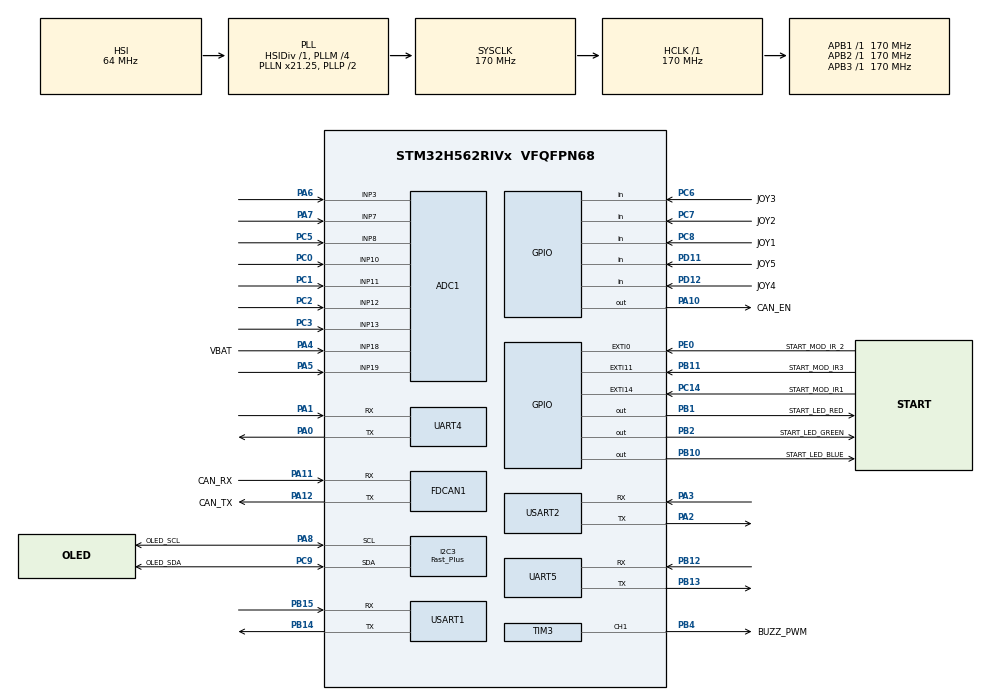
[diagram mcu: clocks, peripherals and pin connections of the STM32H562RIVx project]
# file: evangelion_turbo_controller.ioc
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ADC1.Channel-0\#ChannelRegularConversion=ADC_CHANNEL_3
ADC1.Channel-1\#ChannelRegularConversion=ADC_CHANNEL_7
ADC1.Channel-2\#ChannelRegularConversion=ADC_CHANNEL_8
ADC1.Channel-3\#ChannelRegularConversion=ADC_CHANNEL_10
ADC1.Channel-4\#ChannelRegularConversion=ADC_CHANNEL_11
ADC1.Channel-5\#ChannelRegularConversion=ADC_CHANNEL_12
ADC1.Channel-6\#ChannelRegularConversion=ADC_CHANNEL_13
ADC1.Channel-7\#ChannelRegularConversion=ADC_CHANNEL_18
ADC1.Channel-8\#ChannelRegularConversion=ADC_CHANNEL_19
ADC1.ContinuousConvMode=ENABLE
ADC1.ConversionDataManagement=ADC_CONVERSIONDATA_DMA_CIRCULAR
ADC1.DMAContinuousRequests=ENABLE
ADC1.MonitoredBy-0\#ChannelRegularConversion=__NULL
ADC1.MonitoredBy-1\#ChannelRegularConversion=__NULL
ADC1.MonitoredBy-2\#ChannelRegularConversion=__NULL
ADC1.MonitoredBy-3\#ChannelRegularConversion=__NULL
ADC1.MonitoredBy-4\#ChannelRegularConversion=__NULL
ADC1.MonitoredBy-5\#ChannelRegularConversion=__NULL
ADC1.MonitoredBy-6\#ChannelRegularConversion=__NULL
ADC1.MonitoredBy-7\#ChannelRegularConversion=__NULL
ADC1.MonitoredBy-8\#ChannelRegularConversion=__NULL
ADC1.NbrOfConversion=9
ADC1.NbrOfConversionFlag=1
ADC1.OffsetNumber-0\#ChannelRegularConversion=ADC_OFFSET_NONE
ADC1.OffsetNumber-1\#ChannelRegularConversion=ADC_OFFSET_NONE
ADC1.OffsetNumber-2\#ChannelRegularConversion=ADC_OFFSET_NONE
ADC1.OffsetNumber-3\#ChannelRegularConversion=ADC_OFFSET_NONE
ADC1.OffsetNumber-4\#ChannelRegularConversion=ADC_OFFSET_NONE
ADC1.OffsetNumber-5\#ChannelRegularConversion=ADC_OFFSET_NONE
ADC1.OffsetNumber-6\#ChannelRegularConversion=ADC_OFFSET_NONE
ADC1.OffsetNumber-7\#ChannelRegularConversion=ADC_OFFSET_NONE
ADC1.OffsetNumber-8\#ChannelRegularConversion=ADC_OFFSET_NONE
ADC1.Overrun=ADC_OVR_DATA_OVERWRITTEN
ADC1.Rank-0\#ChannelRegularConversion=1
ADC1.Rank-1\#ChannelRegularConversion=2
ADC1.Rank-2\#ChannelRegularConversion=3
ADC1.Rank-3\#ChannelRegularConversion=4
ADC1.Rank-4\#ChannelRegularConversion=5
ADC1.Rank-5\#ChannelRegularConversion=6
ADC1.Rank-6\#ChannelRegularConversion=7
ADC1.Rank-7\#ChannelRegularConversion=8
ADC1.Rank-8\#ChannelRegularConversion=9
ADC1.SamplingTime-0\#ChannelRegularConversion=ADC_SAMPLETIME_24CYCLES_5
ADC1.SamplingTime-1\#ChannelRegularConversion=ADC_SAMPLETIME_24CYCLES_5
ADC1.SamplingTime-2\#ChannelRegularConversion=ADC_SAMPLETIME_24CYCLES_5
ADC1.SamplingTime-3\#ChannelRegularConversion=ADC_SAMPLETIME_24CYCLES_5
ADC1.SamplingTime-4\#ChannelRegularConversion=ADC_SAMPLETIME_24CYCLES_5
ADC1.SamplingTime-5\#ChannelRegularConversion=ADC_SAMPLETIME_24CYCLES_5
ADC1.SamplingTime-6\#ChannelRegularConversion=ADC_SAMPLETIME_24CYCLES_5
ADC1.SamplingTime-7\#ChannelRegularConversion=ADC_SAMPLETIME_24CYCLES_5
ADC1.SamplingTime-8\#ChannelRegularConversion=ADC_SAMPLETIME_24CYCLES_5
ADC1.master=1
BOOTPATH.BootPathName=LEGACY
BOOTPATH.UserSelectedBootPath=LEGACY
CORTEX_M33_NS.userName=CORTEX_M33
FDCAN1.CalculateBaudRateNominal=1000000
FDCAN1.CalculateTimeBitNominal=1000
FDCAN1.CalculateTimeQuantumNominal=200.0
FDCAN1.DataPrescaler=17
FDCAN1.DataTimeSeg1=2
FDCAN1.DataTimeSeg2=2
FDCAN1.FrameFormat=FDCAN_FRAME_FD_BRS
FDCAN1.NominalPrescaler=34
FDCAN1.NominalTimeSeg1=2
FDCAN1.NominalTimeSeg2=2
GPDMA1.CIRCULARMODE_GPDMACH1=DISABLE
GPDMA1.CIRCULARMODE_GPDMACH2=DISABLE
GPDMA1.CIRCULARMODE_GPDMACH4=DISABLE
GPDMA1.CIRCULARMODE_GPDMACH5=DISABLE
GPDMA1.DATAHANDLING_GPDMACH2=NONE
GPDMA1.DESTBURSTLENGTH_GPDMACH2=1
GPDMA1.DESTDATAWIDTH_GPDMACH2=DMA_DEST_DATAWIDTH_BYTE
GPDMA1.DESTINC_GPDMACH1=DMA_DINC_INCREMENTED
GPDMA1.DESTINC_GPDMACH2=DMA_DINC_INCREMENTED
GPDMA1.DESTINC_GPDMACH4=DMA_DINC_INCREMENTED
GPDMA1.DESTINC_GPDMACH5=DMA_DINC_INCREMENTED
GPDMA1.IPHANDLE_GPDMACH1-SIMPLEREQUEST_GPDMACH1=__NULL
GPDMA1.IPHANDLE_GPDMACH2-SIMPLEREQUEST_GPDMACH2=__NULL
GPDMA1.IPHANDLE_GPDMACH4-SIMPLEREQUEST_GPDMACH4=__NULL
GPDMA1.IPHANDLE_GPDMACH5-SIMPLEREQUEST_GPDMACH5=__NULL
GPDMA1.LINKALLOCATEDPORT_CIRCULAR_GPDMACH4=DMA_LINK_ALLOCATED_PORT1
GPDMA1.LINKALLOCATEDPORT_CIRCULAR_GPDMACH5=DMA_LINK_ALLOCATED_PORT1
GPDMA1.PRIORITY_GPDMACH1=DMA_LOW_PRIORITY_HIGH_WEIGHT
GPDMA1.PRIORITY_GPDMACH2=DMA_LOW_PRIORITY_HIGH_WEIGHT
GPDMA1.PRIORITY_GPDMACH4=DMA_LOW_PRIORITY_HIGH_WEIGHT
GPDMA1.PRIORITY_GPDMACH5=DMA_LOW_PRIORITY_HIGH_WEIGHT
GPDMA1.REQUEST_GPDMACH1=GPDMA1_REQUEST_USART1_RX
GPDMA1.REQUEST_GPDMACH2=GPDMA1_REQUEST_USART2_RX
GPDMA1.REQUEST_GPDMACH4=GPDMA1_REQUEST_UART4_RX
GPDMA1.REQUEST_GPDMACH5=GPDMA1_REQUEST_UART5_RX
GPDMA1.SRCBURSTLENGTH_GPDMACH2=1
GPDMA1.SRCDATAWIDTH_GPDMACH1=DMA_SRC_DATAWIDTH_BYTE
GPDMA1.SRCDATAWIDTH_GPDMACH2=DMA_SRC_DATAWIDTH_BYTE
GPDMA1.SRCINC_GPDMACH2=DMA_SINC_FIXED
GPDMA2.CIRCULARMODE_GPDMACH0=ENABLE
GPDMA2.DESTDATAWIDTH_GPDMACH0=DMA_DEST_DATAWIDTH_HALFWORD
GPDMA2.DESTINC_GPDMACH0=DMA_DINC_INCREMENTED
GPDMA2.IPHANDLE_GPDMACH0-SIMPLEREQUEST_GPDMACH0=__NULL
GPDMA2.LINKALLOCATEDPORT_CIRCULAR_GPDMACH0=DMA_LINK_ALLOCATED_PORT1
GPDMA2.PRIORITY_LL_CIRCULAR_GPDMACH0=DMA_LOW_PRIORITY_MID_WEIGHT
GPDMA2.REQUEST_GPDMACH0=GPDMA2_REQUEST_ADC1
GPDMA2.SRCDATAWIDTH_GPDMACH0=DMA_SRC_DATAWIDTH_HALFWORD
I2C3.I2C_Speed_Mode=I2C_Fast_Plus
I2C3.Timing=0x00802172
Mcu.Family=STM32H5
Mcu.Name=STM32H562RIVx
Mcu.Package=VFQFPN68
NVIC.FDCAN1_IT0_IRQn=true\:0\:0\:false\:false\:true\:true\:true\:true
NVIC.FDCAN1_IT1_IRQn=true\:0\:0\:false\:false\:true\:true\:true\:true
NVIC.GPDMA1_Channel1_IRQn=true\:0\:0\:false\:false\:true\:false\:true\:true
NVIC.GPDMA1_Channel2_IRQn=true\:0\:0\:false\:false\:true\:false\:true\:true
NVIC.GPDMA1_Channel4_IRQn=true\:0\:0\:false\:false\:true\:false\:true\:true
NVIC.GPDMA1_Channel5_IRQn=true\:0\:0\:false\:false\:true\:false\:true\:true
NVIC.GPDMA2_Channel0_IRQn=true\:0\:0\:false\:false\:true\:false\:true\:true
NVIC.I2C3_ER_IRQn=true\:0\:0\:false\:false\:true\:true\:true\:true
NVIC.I2C3_EV_IRQn=true\:0\:0\:false\:false\:true\:true\:true\:true
NVIC.PriorityGroup=NVIC_PRIORITYGROUP_4
NVIC.TIM15_IRQn=true\:0\:0\:false\:false\:true\:true\:true\:true
NVIC.TIM16_IRQn=true\:0\:0\:false\:false\:true\:true\:true\:true
NVIC.TIM17_IRQn=true\:0\:0\:false\:false\:true\:true\:true\:true
NVIC.UART4_IRQn=true\:0\:0\:false\:false\:true\:true\:true\:true
NVIC.UART5_IRQn=true\:0\:0\:false\:false\:true\:true\:true\:true
NVIC.USART1_IRQn=true\:0\:0\:false\:false\:true\:true\:true\:true
NVIC.USART2_IRQn=true\:0\:0\:false\:false\:true\:true\:true\:true
PA0.Mode=Asynchronous
PA0.Signal=UART4_TX
PA1.Mode=Asynchronous
PA1.PinAttribute=Free
PA1.Signal=UART4_RX
PA10.GPIO_Label=CAN_EN
PA10.PinAttribute=Free
PA10.Signal=GPIO_Output
PA11.GPIO_Label=CAN_RX
PA11.Mode=FDCAN_Activate
PA11.PinAttribute=Free
PA11.Signal=FDCAN1_RX
PA12.GPIO_Label=CAN_TX
PA12.Mode=FDCAN_Activate
PA12.PinAttribute=Free
PA12.Signal=FDCAN1_TX
PA13(JTMS/SWDIO).Mode=Serial_Wire
PA13(JTMS/SWDIO).Signal=DEBUG_JTMS-SWDIO
PA14(JTCK/SWCLK).Mode=Serial_Wire
PA14(JTCK/SWCLK).Signal=DEBUG_JTCK-SWCLK
PA2.Mode=Asynchronous
PA2.PinAttribute=Free
PA2.Signal=USART2_TX
PA3.Mode=Asynchronous
PA3.PinAttribute=Free
PA3.Signal=USART2_RX
PA4.GPIO_Label=VBAT
PA4.PinAttribute=Free
PA4.Signal=ADCx_INP18
PA5.PinAttribute=Free
PA5.Signal=ADCx_INP19
PA6.PinAttribute=Free
PA6.Signal=ADCx_INP3
PA7.PinAttribute=Free
PA7.Signal=ADCx_INP7
PA8.GPIO_Label=OLED_SCL
PA8.Mode=I2C
PA8.PinAttribute=Free
PA8.Signal=I2C3_SCL
PB1.GPIO_Label=START_LED_RED
PB1.PinAttribute=Free
PB1.Signal=GPIO_Output
PB10.GPIO_Label=START_LED_BLUE
PB10.PinAttribute=Free
PB10.Signal=GPIO_Output
PB11.GPIO_Label=START_MOD_IR3
PB11.PinAttribute=Free
PB11.Signal=GPXTI11
PB12.Mode=Asynchronous
PB12.PinAttribute=Free
PB12.Signal=UART5_RX
PB13.Mode=Asynchronous
PB13.PinAttribute=Free
PB13.Signal=UART5_TX
PB14.Mode=Asynchronous
PB14.PinAttribute=Free
PB14.Signal=USART1_TX
PB15.Mode=Asynchronous
PB15.PinAttribute=Free
PB15.Signal=USART1_RX
PB2.GPIO_Label=START_LED_GREEN
PB2.PinAttribute=Free
PB2.Signal=GPIO_Output
PB4(NJTRST).GPIO_Label=BUZZ_PWM
PB4(NJTRST).PinAttribute=Free
PB4(NJTRST).Signal=S_TIM3_CH1
PC0.PinAttribute=Free
PC0.Signal=ADCx_INP10
PC1.Signal=ADCx_INP11
PC14-OSC32_IN(OSC32_IN).GPIO_Label=START_MOD_IR1
PC14-OSC32_IN(OSC32_IN).Signal=GPXTI14
PC2.Signal=ADCx_INP12
PC3.Signal=ADCx_INP13
PC5.PinAttribute=Free
PC5.Signal=ADCx_INP8
PC6.GPIO_Label=JOY3
PC6.PinAttribute=Free
PC6.Signal=GPIO_Input
PC7.GPIO_Label=JOY2
PC7.PinAttribute=Free
PC7.Signal=GPIO_Input
PC8.GPIO_Label=JOY1
PC8.PinAttribute=Free
PC8.Signal=GPIO_Input
PC9.GPIO_Label=OLED_SDA
PC9.Mode=I2C
PC9.PinAttribute=Free
PC9.Signal=I2C3_SDA
PD11.GPIO_Label=JOY5
PD11.PinAttribute=Free
PD11.Signal=GPIO_Input
PD12.GPIO_Label=JOY4
PD12.PinAttribute=Free
PD12.Signal=GPIO_Input
PE0.GPIO_Label=START_MOD_IR_2
PE0.PinAttribute=Free
PE0.Signal=GPXTI0
ProjectManager.HeapSize=0x200
ProjectManager.StackSize=0x400
ProjectManager.TargetToolchain=STM32CubeIDE
RCC.ADCFreq_Value=170000000
RCC.AHBFreq_Value=170000000
RCC.APB1Freq_Value=170000000
RCC.APB1TimFreq_Value=170000000
RCC.APB2Freq_Value=170000000
RCC.APB2TimFreq_Value=170000000
RCC.APB3Freq_Value=170000000
RCC.CSI_VALUE=4000000
RCC.CortexFreq_Value=170000000
RCC.EPOD_VALUE=64000000
RCC.FDCANClockSelection=RCC_FDCANCLKSOURCE_PLL1Q
RCC.HCLKFreq_Value=170000000
RCC.HSE_Timout=200
RCC.HSE_VALUE=48000000
RCC.HSI48_VALUE=48000000
RCC.HSIDiv=RCC_HSI_DIV1
RCC.HSI_VALUE=64000000
RCC.LSE_VALUE=32768
RCC.LSIRC_VALUE=32000
RCC.PLL2FRACN=0
RCC.PLL2Source=RCC_PLL2_SOURCE_HSI
RCC.PLL3FRACN=0
RCC.PLL3Source=RCC_PLL3_SOURCE_HSI
RCC.PLL3_VCI_Range-AdvancedSettings=RCC_PLL3_VCIRANGE_0
RCC.PLLFRACN=2048
RCC.PLLM=4
RCC.PLLN=21
RCC.PLLSourceVirtual=RCC_PLL1_SOURCE_HSI
RCC.SYSCLKFreq_VALUE=170000000
RCC.SYSCLKSource=RCC_SYSCLKSOURCE_PLLCLK
RCC.USBFreq_Value=48000000
RCC.VCOOutputFreq_Value=340000000
SH.ADCx_INP10.0=ADC1_INP10,IN10-Single-Ended
SH.ADCx_INP11.0=ADC1_INP11,IN11-Single-Ended
SH.ADCx_INP12.0=ADC1_INP12,IN12-Single-Ended
SH.ADCx_INP13.0=ADC1_INP13,IN13-Single-Ended
SH.ADCx_INP18.0=ADC1_INP18,IN18-Single-Ended
SH.ADCx_INP19.0=ADC1_INP19,IN19-Single-Ended
SH.ADCx_INP3.0=ADC1_INP3,IN3-Single-Ended
SH.ADCx_INP7.0=ADC1_INP7,IN7-Single-Ended
SH.ADCx_INP8.0=ADC1_INP8,IN8-Single-Ended
SH.S_TIM3_CH1.0=TIM3_CH1,PWM Generation1 CH1
TIM15.PeriodNoDither=10000-1
TIM15.Prescaler=34000-1
TIM16.PeriodNoDither=1000-1
TIM16.Prescaler=170-1
TIM17.PeriodNoDither=1000-1
TIM17.Prescaler=1700-1
TIM3.Channel-PWM\ Generation1\ CH1=TIM_CHANNEL_1
USART1.VirtualMode-Asynchronous=VM_ASYNC
USART2.VirtualMode-Asynchronous=VM_ASYNC
VP_BOOTPATH_VS_BOOTPATH.Mode=BP_Activate
VP_CORTEX_M33_NS_VS_Hclk.Mode=Hclk_Mode
VP_GPDMA1_VS_GPDMACH1.Mode=SIMPLEREQUEST_GPDMACH1
VP_GPDMA1_VS_GPDMACH2.Mode=SIMPLEREQUEST_GPDMACH2
VP_GPDMA1_VS_GPDMACH4.Mode=SIMPLEREQUEST_GPDMACH4
VP_GPDMA1_VS_GPDMACH5.Mode=SIMPLEREQUEST_GPDMACH5
VP_GPDMA2_VS_GPDMACH0.Mode=SIMPLEREQUEST_GPDMACH0
VP_MEMORYMAP_VS_MEMORYMAP.Mode=CurAppReg
VP_PWR_VS_LPOM.Mode=PowerOptimisation
VP_PWR_VS_SECSignals.Mode=Security/Privilege
VP_TIM15_VS_ClockSourceINT.Mode=Internal
VP_TIM16_VS_ClockSourceINT.Mode=Enable_Timer
VP_TIM17_VS_ClockSourceINT.Mode=Enable_Timer
board=custom

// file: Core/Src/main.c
/* USER CODE BEGIN Header */
/**
  ******************************************************************************
  * @file           : main.c
  * @brief          : Main program body
  ******************************************************************************
  * @attention
  *
  * Copyright (c) 2026 STMicroelectronics.
  * All rights reserved.
  *
  * This software is licensed under terms that can be found in the LICENSE file
  * in the root directory of this software component.
  * If no LICENSE file comes with this software, it is provided AS-IS.
  *
  ******************************************************************************
  */
/* USER CODE END Header */
#include "main.h"

/* USER CODE BEGIN Includes */
#include "stdlib.h"
#include "MY_INCLUDES.h"
/* USER CODE END Includes */

/* USER CODE BEGIN PD */
#define CAN_SELF_ID 0x0A
#define CAN_MOTOR_DRIVER_A_ID 0x0B
#define CAN_MOTOR_DRIVER_B_ID 0x0C

#define DMA_HANDLE_UART1 &handle_GPDMA1_Channel1
#define DMA_HANDLE_UART2 &handle_GPDMA1_Channel2
#define DMA_HANDLE_UART4 &handle_GPDMA1_Channel4
#define DMA_HANDLE_UART5 &handle_GPDMA1_Channel5
/* USER CODE END PD */

/* USER CODE BEGIN PM */
typedef struct {
	uint8_t DONT_USE_MOTORS;
	uint8_t ALWAYS_IN_BATTLE;
	uint8_t IGNORE_START_MODULE;
	uint8_t LINE_SENSORS_ALWAYS_IN;
	uint8_t IGNORE_ACCEL;
	uint8_t DONT_INITIALIZE_LIDARS;
} Settings_t;

typedef enum {
	IN,
	OUT
} LineState_t;

typedef enum {
	STRAIGHT,
	CURVE,
	FOLLOW_LINER, //todo MRUGNIJ TYLE RAZY JAKI TRYB PO GUZIKU?
} RobotAttackMode_t;

typedef enum
{
	IDLE,
	ATTACK,
	BEFORE_ATTACK_TASK
} RobotState_t;

typedef enum {
	NOTHING,
	UP_LEFT,
	UP_RIGHT,
	DOWN_LEFT,
	DOWN_RIGHT,
	CENTER,
	BUTTON_REBOUNCE,
} JoystickMode_t;

typedef struct {
	LineState_t Line;
	uint16_t RawLineA;
	uint16_t RawLineB;
    uint16_t Distance;
    uint16_t LidarAmp;
    uint16_t LidarTemp;
} SensorData_t;

typedef struct {
	uint8_t Switch1;
	uint8_t Switch2;
	uint8_t Switch3;
	JoystickMode_t Joystick;
	uint8_t MenuOption;
} Interface_t;

typedef struct
{
	int16_t x;
	int16_t y;
	int16_t z;
	int16_t peak;
} Vector_t;

typedef struct {
	uint8_t inBattle;
	RobotAttackMode_t AttackMode;
	uint16_t Voltage;
	uint16_t CellVoltage;
	RobotState_t State;
	Interface_t Interface;
	uint8_t BattType;
} RobotData_t;

typedef struct {
	uint8_t CurrentAddres;
	uint8_t Started;
	uint8_t StartedViaInterface;
	uint8_t StartedViaSwitch;
	uint16_t Delay;
	uint16_t VolatileDelayTimer;
} StartModData_t;

typedef struct
{
	int8_t L;
	int8_t R;
} Speed_t;

typedef struct
{
	Speed_t Requested;
	Speed_t Set;
} MotorSpeed_t;

typedef struct {
    const char *name;
    uint8_t id;
} MenuOption_t;

/* USER CODE END PM */

ADC_HandleTypeDef hadc1;
DMA_NodeTypeDef Node_GPDMA2_Channel0;
DMA_QListTypeDef List_GPDMA2_Channel0;
DMA_HandleTypeDef handle_GPDMA2_Channel0;

FDCAN_HandleTypeDef hfdcan1;

I2C_HandleTypeDef hi2c3;

TIM_HandleTypeDef htim3;
TIM_HandleTypeDef htim15;
TIM_HandleTypeDef htim16;
TIM_HandleTypeDef htim17;

UART_HandleTypeDef huart4;
UART_HandleTypeDef huart5;
UART_HandleTypeDef huart1;
UART_HandleTypeDef huart2;
DMA_HandleTypeDef handle_GPDMA1_Channel4;
DMA_HandleTypeDef handle_GPDMA1_Channel5;
DMA_HandleTypeDef handle_GPDMA1_Channel1;
DMA_HandleTypeDef handle_GPDMA1_Channel2;

/* USER CODE BEGIN PV */
//CAN
FDCAN_RxHeaderTypeDef 		CAN_RX_Header; 		//CAN Bus Transmit Header
FDCAN_TxHeaderTypeDef 		CAN_TX_Header; 		//CAN Bus Receive Header
uint8_t                     CAN_TX[8];
uint8_t                     CAN_RX[8];
FDCAN_FilterTypeDef 		CAN_Filter;

volatile int32_t dupa=-21;
uint16_t actual_init_freq=FREQ_STARTING;
int16_t ERROR_FLAG=0;

//sensors
uint8_t  UART1_RX[9];
uint8_t  UART2_RX[9];
uint8_t  UART4_RX[9];
uint8_t  UART5_RX[9];
uint8_t  UART_TX[9];

SensorData_t FrontLeft={0};
SensorData_t FrontRight={0};
SensorData_t BackLeft={0};
SensorData_t BackRight={0};
RobotData_t Eva={0};
MotorSpeed_t Motors={0};
StartModData_t StartMod={0};
Settings_t Settings={0};

uint8_t lastSeen = LEFT;
uint8_t before_attack_rotation_direction = LEFT;

volatile uint16_t ADC_BUFFER[9];
float BATTERY_CONSTANT;

uint8_t FLAG_BLINK_RED = 0;
uint8_t FLAG_BLINK_BLUE = 0;
uint8_t FLAG_BLINK_GREEN = 0;

/* USER CODE END PV */

void SystemClock_Config(void);
static void MX_GPIO_Init(void);
static void MX_GPDMA1_Init(void);
static void MX_GPDMA2_Init(void);
static void MX_ADC1_Init(void);
static void MX_FDCAN1_Init(void);
static void MX_I2C3_Init(void);
static void MX_TIM3_Init(void);
static void MX_UART4_Init(void);
static void MX_UART5_Init(void);
static void MX_USART2_UART_Init(void);
static void MX_USART1_UART_Init(void);
static void MX_TIM16_Init(void);
static void MX_TIM17_Init(void);
static void MX_TIM15_Init(void);
/* USER CODE BEGIN PFP */
static void LIDARS_INIT(UART_HandleTypeDef *huart, DMA_HandleTypeDef *hdma, uint8_t *RX);
static void PLAY_FREQ(uint16_t f_hz);
static void COOKED(uint8_t error_code);
static void SORT(uint16_t *array, uint8_t length);
static void GET_LINE_SENSORS(void);
static void GET_START_MOD(void);
static void BATTLE(void);
static void WATCHDOG(void);
static void GET_LAST_SEEN_ROTATIONE(void);
static void TASK_BEFORE_ATTACK(void);
static void LED_BLINK_INTERUPT(void);
static void SET_MOTORS(int8_t l, int8_t r);
/* USER CODE END PFP */

int main(void)
{

  /* MCU Configuration--------------------------------------------------------*/

  /* Reset of all peripherals, Initializes the Flash interface and the Systick. */
  HAL_Init();

  /* USER CODE BEGIN Init */
  HAL_Delay(100);
  /* USER CODE END Init */

  /* Configure the system clock */
  SystemClock_Config();

  /* Initialize all configured peripherals */
  MX_GPIO_Init();
  MX_GPDMA1_Init();
  MX_GPDMA2_Init();
  MX_ADC1_Init();
  MX_FDCAN1_Init();
  MX_I2C3_Init();
  MX_TIM3_Init();
  MX_UART4_Init();
  MX_UART5_Init();
  MX_USART2_UART_Init();
  MX_USART1_UART_Init();
  MX_TIM16_Init();
  MX_TIM17_Init();
  MX_TIM15_Init();
  /* USER CODE BEGIN 2 */

  CAN_Filter.IdType = FDCAN_STANDARD_ID;
  CAN_Filter.FilterIndex = 0;
  CAN_Filter.FilterType = FDCAN_FILTER_DISABLE;
  CAN_Filter.FilterConfig = FDCAN_FILTER_TO_RXFIFO0;
  CAN_Filter.FilterID1 = 0;
  CAN_Filter.FilterID2 = 0;

 // CAN_TX_Header.Identifier = CAN_SELF_ID;
  CAN_TX_Header.Identifier = 0x0B;
  CAN_TX_Header.IdType = FDCAN_STANDARD_ID;
  CAN_TX_Header.TxFrameType = FDCAN_DATA_FRAME;
  CAN_TX_Header.DataLength = FDCAN_DLC_BYTES_8;
  CAN_TX_Header.ErrorStateIndicator = FDCAN_ESI_ACTIVE;
  CAN_TX_Header.BitRateSwitch = FDCAN_BRS_ON;
  CAN_TX_Header.FDFormat = FDCAN_FD_CAN;
  CAN_TX_Header.TxEventFifoControl = FDCAN_NO_TX_EVENTS;
  CAN_TX_Header.MessageMarker = 0;

  BATTERY_CONSTANT = ((Voltage_Resistor_Top + Voltage_Resistor_Bottom) / Voltage_Resistor_Bottom) * Reference_Voltage / 4096;

  Settings.ALWAYS_IN_BATTLE = DEFAULT_SETTING_ALWAYS_IN_BATTLE;
  Settings.DONT_INITIALIZE_LIDARS = DEFAULT_SETTING_DONT_INITIALIZE_LIDARS;
  Settings.DONT_USE_MOTORS = DEFAULT_SETTING_DONT_USE_MOTORS;
  Settings.IGNORE_START_MODULE = DEFAULT_SETTING_IGNORE_START_MODULE;

  lastSeen = LEFT;

  //HAL_FDCAN_Start(&hfdcan1);
  //HAL_FDCAN_ActivateNotification(&hfdcan1, FDCAN_IT_RX_FIFO0_NEW_MESSAGE, 0);

  //CAN_TX_Header.Identifier = CAN_MOTOR_DRIVER_A_ID;
  /*
  while(true)
  {
	  CAN_TX[0] = 0x1C;
	  CAN_TX[1] = 0x1C;
	  HAL_FDCAN_AddMessageToTxFifoQ(&hfdcan1, &CAN_TX_Header, CAN_TX);
	  HAL_Delay(1000);
  }

  */
    //GPIO LED MISC
	actual_init_freq = actual_init_freq + FREQ_STEP_INIT;
	PLAY_FREQ(actual_init_freq);
	HAL_GPIO_WritePin(START_LED_RED_GPIO_Port, START_LED_RED_Pin, 0);
	HAL_GPIO_WritePin(START_LED_BLUE_GPIO_Port, START_LED_BLUE_Pin, 0);
	HAL_GPIO_WritePin(START_LED_GREEN_GPIO_Port, START_LED_GREEN_Pin, 1);

	//LUNAS
	LIDARS_INIT(&huart2, DMA_HANDLE_UART2, UART2_RX);

	//Interrupts
	HAL_TIM_Base_Start_IT(&htim15); //0.5Hz
	HAL_TIM_Base_Start_IT(&htim16); //1000Hz
	HAL_TIM_Base_Start_IT(&htim17); //100Hz

	//ADC
	if (HAL_ADCEx_Calibration_Start(&hadc1, ADC_SINGLE_ENDED) != HAL_OK)
	  COOKED(ADC_INIT_ERR);
	HAL_Delay(50);

	if (HAL_ADC_Start_DMA(&hadc1, (uint32_t*)ADC_BUFFER, 9) != HAL_OK)
	  COOKED(ADC_INIT_ERR);
  /* USER CODE END 2 */

  /* Infinite loop */
  while (1)
  {

  }
}

void SystemClock_Config(void)
{
  RCC_OscInitTypeDef RCC_OscInitStruct = {0};
  RCC_ClkInitTypeDef RCC_ClkInitStruct = {0};

  /** Configure the main internal regulator output voltage
  */
  __HAL_PWR_VOLTAGESCALING_CONFIG(PWR_REGULATOR_VOLTAGE_SCALE1);

  while(!__HAL_PWR_GET_FLAG(PWR_FLAG_VOSRDY)) {}

  /** Initializes the RCC Oscillators according to the specified parameters
  * in the RCC_OscInitTypeDef structure.
  */
  RCC_OscInitStruct.OscillatorType = RCC_OSCILLATORTYPE_HSI;
  RCC_OscInitStruct.HSIState = RCC_HSI_ON;
  RCC_OscInitStruct.HSIDiv = RCC_HSI_DIV1;
  RCC_OscInitStruct.HSICalibrationValue = RCC_HSICALIBRATION_DEFAULT;
  RCC_OscInitStruct.PLL.PLLState = RCC_PLL_ON;
  RCC_OscInitStruct.PLL.PLLSource = RCC_PLL1_SOURCE_HSI;
  RCC_OscInitStruct.PLL.PLLM = 4;
  RCC_OscInitStruct.PLL.PLLN = 21;
  RCC_OscInitStruct.PLL.PLLP = 2;
  RCC_OscInitStruct.PLL.PLLQ = 2;
  RCC_OscInitStruct.PLL.PLLR = 2;
  RCC_OscInitStruct.PLL.PLLRGE = RCC_PLL1_VCIRANGE_3;
  RCC_OscInitStruct.PLL.PLLVCOSEL = RCC_PLL1_VCORANGE_WIDE;
  RCC_OscInitStruct.PLL.PLLFRACN = 2048;
  if (HAL_RCC_OscConfig(&RCC_OscInitStruct) != HAL_OK)
  {
    Error_Handler();
  }

  /** Initializes the CPU, AHB and APB buses clocks
  */
  RCC_ClkInitStruct.ClockType = RCC_CLOCKTYPE_HCLK|RCC_CLOCKTYPE_SYSCLK
                              |RCC_CLOCKTYPE_PCLK1|RCC_CLOCKTYPE_PCLK2
                              |RCC_CLOCKTYPE_PCLK3;
  RCC_ClkInitStruct.SYSCLKSource = RCC_SYSCLKSOURCE_PLLCLK;
  RCC_ClkInitStruct.AHBCLKDivider = RCC_SYSCLK_DIV1;
  RCC_ClkInitStruct.APB1CLKDivider = RCC_HCLK_DIV1;
  RCC_ClkInitStruct.APB2CLKDivider = RCC_HCLK_DIV1;
  RCC_ClkInitStruct.APB3CLKDivider = RCC_HCLK_DIV1;

  if (HAL_RCC_ClockConfig(&RCC_ClkInitStruct, FLASH_LATENCY_4) != HAL_OK)
  {
    Error_Handler();
  }

  /** Configure the programming delay
  */
  __HAL_FLASH_SET_PROGRAM_DELAY(FLASH_PROGRAMMING_DELAY_2);
}

static void MX_ADC1_Init(void)
{

  ADC_ChannelConfTypeDef sConfig = {0};

  /** Common config
  */
  hadc1.Instance = ADC1;
  hadc1.Init.ClockPrescaler = ADC_CLOCK_ASYNC_DIV4;
  hadc1.Init.Resolution = ADC_RESOLUTION_12B;
  hadc1.Init.DataAlign = ADC_DATAALIGN_RIGHT;
  hadc1.Init.ScanConvMode = ADC_SCAN_ENABLE;
  hadc1.Init.EOCSelection = ADC_EOC_SINGLE_CONV;
  hadc1.Init.LowPowerAutoWait = DISABLE;
  hadc1.Init.ContinuousConvMode = ENABLE;
  hadc1.Init.NbrOfConversion = 9;
  hadc1.Init.DiscontinuousConvMode = DISABLE;
  hadc1.Init.ExternalTrigConv = ADC_SOFTWARE_START;
  hadc1.Init.ExternalTrigConvEdge = ADC_EXTERNALTRIGCONVEDGE_NONE;
  hadc1.Init.DMAContinuousRequests = ENABLE;
  hadc1.Init.SamplingMode = ADC_SAMPLING_MODE_NORMAL;
  hadc1.Init.Overrun = ADC_OVR_DATA_OVERWRITTEN;
  hadc1.Init.OversamplingMode = DISABLE;
  if (HAL_ADC_Init(&hadc1) != HAL_OK)
  {
    Error_Handler();
  }

  /** Configure Regular Channel
  */
  sConfig.Channel = ADC_CHANNEL_3;
  sConfig.Rank = ADC_REGULAR_RANK_1;
  sConfig.SamplingTime = ADC_SAMPLETIME_24CYCLES_5;
  sConfig.SingleDiff = ADC_SINGLE_ENDED;
  sConfig.OffsetNumber = ADC_OFFSET_NONE;
  sConfig.Offset = 0;
  if (HAL_ADC_ConfigChannel(&hadc1, &sConfig) != HAL_OK)
  {
    Error_Handler();
  }

  /** Configure Regular Channel
  */
  sConfig.Channel = ADC_CHANNEL_7;
  sConfig.Rank = ADC_REGULAR_RANK_2;
  if (HAL_ADC_ConfigChannel(&hadc1, &sConfig) != HAL_OK)
  {
    Error_Handler();
  }

  /** Configure Regular Channel
  */
  sConfig.Channel = ADC_CHANNEL_8;
  sConfig.Rank = ADC_REGULAR_RANK_3;
  if (HAL_ADC_ConfigChannel(&hadc1, &sConfig) != HAL_OK)
  {
    Error_Handler();
  }

  /** Configure Regular Channel
  */
  sConfig.Channel = ADC_CHANNEL_10;
  sConfig.Rank = ADC_REGULAR_RANK_4;
  if (HAL_ADC_ConfigChannel(&hadc1, &sConfig) != HAL_OK)
  {
    Error_Handler();
  }

  /** Configure Regular Channel
  */
  sConfig.Channel = ADC_CHANNEL_11;
  sConfig.Rank = ADC_REGULAR_RANK_5;
  if (HAL_ADC_ConfigChannel(&hadc1, &sConfig) != HAL_OK)
  {
    Error_Handler();
  }

  /** Configure Regular Channel
  */
  sConfig.Channel = ADC_CHANNEL_12;
  sConfig.Rank = ADC_REGULAR_RANK_6;
  if (HAL_ADC_ConfigChannel(&hadc1, &sConfig) != HAL_OK)
  {
    Error_Handler();
  }

  /** Configure Regular Channel
  */
  sConfig.Channel = ADC_CHANNEL_13;
  sConfig.Rank = ADC_REGULAR_RANK_7;
  if (HAL_ADC_ConfigChannel(&hadc1, &sConfig) != HAL_OK)
  {
    Error_Handler();
  }

  /** Configure Regular Channel
  */
  sConfig.Channel = ADC_CHANNEL_18;
  sConfig.Rank = ADC_REGULAR_RANK_8;
  if (HAL_ADC_ConfigChannel(&hadc1, &sConfig) != HAL_OK)
  {
    Error_Handler();
  }

  /** Configure Regular Channel
  */
  sConfig.Channel = ADC_CHANNEL_19;
  sConfig.Rank = ADC_REGULAR_RANK_9;
  if (HAL_ADC_ConfigChannel(&hadc1, &sConfig) != HAL_OK)
  {
    Error_Handler();
  }

}

static void MX_FDCAN1_Init(void)
{

  hfdcan1.Instance = FDCAN1;
  hfdcan1.Init.ClockDivider = FDCAN_CLOCK_DIV1;
  hfdcan1.Init.FrameFormat = FDCAN_FRAME_FD_BRS;
  hfdcan1.Init.Mode = FDCAN_MODE_NORMAL;
  hfdcan1.Init.AutoRetransmission = DISABLE;
  hfdcan1.Init.TransmitPause = DISABLE;
  hfdcan1.Init.ProtocolException = DISABLE;
  hfdcan1.Init.NominalPrescaler = 34;
  hfdcan1.Init.NominalSyncJumpWidth = 1;
  hfdcan1.Init.NominalTimeSeg1 = 2;
  hfdcan1.Init.NominalTimeSeg2 = 2;
  hfdcan1.Init.DataPrescaler = 17;
  hfdcan1.Init.DataSyncJumpWidth = 1;
  hfdcan1.Init.DataTimeSeg1 = 2;
  hfdcan1.Init.DataTimeSeg2 = 2;
  hfdcan1.Init.StdFiltersNbr = 0;
  hfdcan1.Init.ExtFiltersNbr = 0;
  hfdcan1.Init.TxFifoQueueMode = FDCAN_TX_FIFO_OPERATION;
  if (HAL_FDCAN_Init(&hfdcan1) != HAL_OK)
  {
    Error_Handler();
  }

}

static void MX_GPDMA1_Init(void)
{

  /* Peripheral clock enable */
  __HAL_RCC_GPDMA1_CLK_ENABLE();

  /* GPDMA1 interrupt Init */
    HAL_NVIC_SetPriority(GPDMA1_Channel1_IRQn, 0, 0);
    HAL_NVIC_EnableIRQ(GPDMA1_Channel1_IRQn);
    HAL_NVIC_SetPriority(GPDMA1_Channel2_IRQn, 0, 0);
    HAL_NVIC_EnableIRQ(GPDMA1_Channel2_IRQn);
    HAL_NVIC_SetPriority(GPDMA1_Channel4_IRQn, 0, 0);
    HAL_NVIC_EnableIRQ(GPDMA1_Channel4_IRQn);
    HAL_NVIC_SetPriority(GPDMA1_Channel5_IRQn, 0, 0);
    HAL_NVIC_EnableIRQ(GPDMA1_Channel5_IRQn);

}

static void MX_GPDMA2_Init(void)
{

  /* Peripheral clock enable */
  __HAL_RCC_GPDMA2_CLK_ENABLE();

  /* GPDMA2 interrupt Init */
    HAL_NVIC_SetPriority(GPDMA2_Channel0_IRQn, 0, 0);
    HAL_NVIC_EnableIRQ(GPDMA2_Channel0_IRQn);

}

static void MX_I2C3_Init(void)
{

  hi2c3.Instance = I2C3;
  hi2c3.Init.Timing = 0x00802172;
  hi2c3.Init.OwnAddress1 = 0;
  hi2c3.Init.AddressingMode = I2C_ADDRESSINGMODE_7BIT;
  hi2c3.Init.DualAddressMode = I2C_DUALADDRESS_DISABLE;
  hi2c3.Init.OwnAddress2 = 0;
  hi2c3.Init.OwnAddress2Masks = I2C_OA2_NOMASK;
  hi2c3.Init.GeneralCallMode = I2C_GENERALCALL_DISABLE;
  hi2c3.Init.NoStretchMode = I2C_NOSTRETCH_DISABLE;
  if (HAL_I2C_Init(&hi2c3) != HAL_OK)
  {
    Error_Handler();
  }

  /** Configure Analogue filter
  */
  if (HAL_I2CEx_ConfigAnalogFilter(&hi2c3, I2C_ANALOGFILTER_ENABLE) != HAL_OK)
  {
    Error_Handler();
  }

  /** Configure Digital filter
  */
  if (HAL_I2CEx_ConfigDigitalFilter(&hi2c3, 0) != HAL_OK)
  {
    Error_Handler();
  }

  /** I2C Fast mode Plus enable
  */
  if (HAL_I2CEx_ConfigFastModePlus(&hi2c3, I2C_FASTMODEPLUS_ENABLE) != HAL_OK)
  {
    Error_Handler();
  }

}

static void MX_TIM3_Init(void)
{

  TIM_MasterConfigTypeDef sMasterConfig = {0};
  TIM_OC_InitTypeDef sConfigOC = {0};

  htim3.Instance = TIM3;
  htim3.Init.Prescaler = 0;
  htim3.Init.CounterMode = TIM_COUNTERMODE_UP;
  htim3.Init.Period = 65535;
  htim3.Init.ClockDivision = TIM_CLOCKDIVISION_DIV1;
  htim3.Init.AutoReloadPreload = TIM_AUTORELOAD_PRELOAD_DISABLE;
  if (HAL_TIM_PWM_Init(&htim3) != HAL_OK)
  {
    Error_Handler();
  }
  sMasterConfig.MasterOutputTrigger = TIM_TRGO_RESET;
  sMasterConfig.MasterSlaveMode = TIM_MASTERSLAVEMODE_DISABLE;
  if (HAL_TIMEx_MasterConfigSynchronization(&htim3, &sMasterConfig) != HAL_OK)
  {
    Error_Handler();
  }
  sConfigOC.OCMode = TIM_OCMODE_PWM1;
  sConfigOC.Pulse = 0;
  sConfigOC.OCPolarity = TIM_OCPOLARITY_HIGH;
  sConfigOC.OCFastMode = TIM_OCFAST_DISABLE;
  if (HAL_TIM_PWM_ConfigChannel(&htim3, &sConfigOC, TIM_CHANNEL_1) != HAL_OK)
  {
    Error_Handler();
  }
  HAL_TIM_MspPostInit(&htim3);

}

static void MX_TIM15_Init(void)
{

  TIM_ClockConfigTypeDef sClockSourceConfig = {0};
  TIM_MasterConfigTypeDef sMasterConfig = {0};

  htim15.Instance = TIM15;
  htim15.Init.Prescaler = 34000-1;
  htim15.Init.CounterMode = TIM_COUNTERMODE_UP;
  htim15.Init.Period = 9999;
  htim15.Init.ClockDivision = TIM_CLOCKDIVISION_DIV1;
  htim15.Init.RepetitionCounter = 0;
  htim15.Init.AutoReloadPreload = TIM_AUTORELOAD_PRELOAD_DISABLE;
  if (HAL_TIM_Base_Init(&htim15) != HAL_OK)
  {
    Error_Handler();
  }
  sClockSourceConfig.ClockSource = TIM_CLOCKSOURCE_INTERNAL;
  if (HAL_TIM_ConfigClockSource(&htim15, &sClockSourceConfig) != HAL_OK)
  {
    Error_Handler();
  }
  sMasterConfig.MasterOutputTrigger = TIM_TRGO_RESET;
  sMasterConfig.MasterSlaveMode = TIM_MASTERSLAVEMODE_DISABLE;
  if (HAL_TIMEx_MasterConfigSynchronization(&htim15, &sMasterConfig) != HAL_OK)
  {
    Error_Handler();
  }

}

static void MX_TIM16_Init(void)
{

  htim16.Instance = TIM16;
  htim16.Init.Prescaler = 170-1;
  htim16.Init.CounterMode = TIM_COUNTERMODE_UP;
  htim16.Init.Period = 999;
  htim16.Init.ClockDivision = TIM_CLOCKDIVISION_DIV1;
  htim16.Init.RepetitionCounter = 0;
  htim16.Init.AutoReloadPreload = TIM_AUTORELOAD_PRELOAD_DISABLE;
  if (HAL_TIM_Base_Init(&htim16) != HAL_OK)
  {
    Error_Handler();
  }

}

static void MX_TIM17_Init(void)
{

  htim17.Instance = TIM17;
  htim17.Init.Prescaler = 1700-1;
  htim17.Init.CounterMode = TIM_COUNTERMODE_UP;
  htim17.Init.Period = 999;
  htim17.Init.ClockDivision = TIM_CLOCKDIVISION_DIV1;
  htim17.Init.RepetitionCounter = 0;
  htim17.Init.AutoReloadPreload = TIM_AUTORELOAD_PRELOAD_DISABLE;
  if (HAL_TIM_Base_Init(&htim17) != HAL_OK)
  {
    Error_Handler();
  }

}

static void MX_UART4_Init(void)
{

  huart4.Instance = UART4;
  huart4.Init.BaudRate = 115200;
  huart4.Init.WordLength = UART_WORDLENGTH_8B;
  huart4.Init.StopBits = UART_STOPBITS_1;
  huart4.Init.Parity = UART_PARITY_NONE;
  huart4.Init.Mode = UART_MODE_TX_RX;
  huart4.Init.HwFlowCtl = UART_HWCONTROL_NONE;
  huart4.Init.OverSampling = UART_OVERSAMPLING_16;
  huart4.Init.OneBitSampling = UART_ONE_BIT_SAMPLE_DISABLE;
  huart4.Init.ClockPrescaler = UART_PRESCALER_DIV1;
  huart4.AdvancedInit.AdvFeatureInit = UART_ADVFEATURE_NO_INIT;
  if (HAL_UART_Init(&huart4) != HAL_OK)
  {
    Error_Handler();
  }
  if (HAL_UARTEx_SetTxFifoThreshold(&huart4, UART_TXFIFO_THRESHOLD_1_8) != HAL_OK)
  {
    Error_Handler();
  }
  if (HAL_UARTEx_SetRxFifoThreshold(&huart4, UART_RXFIFO_THRESHOLD_1_8) != HAL_OK)
  {
    Error_Handler();
  }
  if (HAL_UARTEx_DisableFifoMode(&huart4) != HAL_OK)
  {
    Error_Handler();
  }

}

static void MX_UART5_Init(void)
{

  huart5.Instance = UART5;
  huart5.Init.BaudRate = 115200;
  huart5.Init.WordLength = UART_WORDLENGTH_8B;
  huart5.Init.StopBits = UART_STOPBITS_1;
  huart5.Init.Parity = UART_PARITY_NONE;
  huart5.Init.Mode = UART_MODE_TX_RX;
  huart5.Init.HwFlowCtl = UART_HWCONTROL_NONE;
  huart5.Init.OverSampling = UART_OVERSAMPLING_16;
  huart5.Init.OneBitSampling = UART_ONE_BIT_SAMPLE_DISABLE;
  huart5.Init.ClockPrescaler = UART_PRESCALER_DIV1;
  huart5.AdvancedInit.AdvFeatureInit = UART_ADVFEATURE_NO_INIT;
  if (HAL_UART_Init(&huart5) != HAL_OK)
  {
    Error_Handler();
  }
  if (HAL_UARTEx_SetTxFifoThreshold(&huart5, UART_TXFIFO_THRESHOLD_1_8) != HAL_OK)
  {
    Error_Handler();
  }
  if (HAL_UARTEx_SetRxFifoThreshold(&huart5, UART_RXFIFO_THRESHOLD_1_8) != HAL_OK)
  {
    Error_Handler();
  }
  if (HAL_UARTEx_DisableFifoMode(&huart5) != HAL_OK)
  {
    Error_Handler();
  }

}

static void MX_USART1_UART_Init(void)
{

  huart1.Instance = USART1;
  huart1.Init.BaudRate = 115200;
  huart1.Init.WordLength = UART_WORDLENGTH_8B;
  huart1.Init.StopBits = UART_STOPBITS_1;
  huart1.Init.Parity = UART_PARITY_NONE;
  huart1.Init.Mode = UART_MODE_TX_RX;
  huart1.Init.HwFlowCtl = UART_HWCONTROL_NONE;
  huart1.Init.OverSampling = UART_OVERSAMPLING_16;
  huart1.Init.OneBitSampling = UART_ONE_BIT_SAMPLE_DISABLE;
  huart1.Init.ClockPrescaler = UART_PRESCALER_DIV1;
  huart1.AdvancedInit.AdvFeatureInit = UART_ADVFEATURE_NO_INIT;
  if (HAL_UART_Init(&huart1) != HAL_OK)
  {
    Error_Handler();
  }
  if (HAL_UARTEx_SetTxFifoThreshold(&huart1, UART_TXFIFO_THRESHOLD_1_8) != HAL_OK)
  {
    Error_Handler();
  }
  if (HAL_UARTEx_SetRxFifoThreshold(&huart1, UART_RXFIFO_THRESHOLD_1_8) != HAL_OK)
  {
    Error_Handler();
  }
  if (HAL_UARTEx_DisableFifoMode(&huart1) != HAL_OK)
  {
    Error_Handler();
  }

}

static void MX_USART2_UART_Init(void)
{

  huart2.Instance = USART2;
  huart2.Init.BaudRate = 115200;
  huart2.Init.WordLength = UART_WORDLENGTH_8B;
  huart2.Init.StopBits = UART_STOPBITS_1;
  huart2.Init.Parity = UART_PARITY_NONE;
  huart2.Init.Mode = UART_MODE_TX_RX;
  huart2.Init.HwFlowCtl = UART_HWCONTROL_NONE;
  huart2.Init.OverSampling = UART_OVERSAMPLING_16;
  huart2.Init.OneBitSampling = UART_ONE_BIT_SAMPLE_DISABLE;
  huart2.Init.ClockPrescaler = UART_PRESCALER_DIV1;
  huart2.AdvancedInit.AdvFeatureInit = UART_ADVFEATURE_NO_INIT;
  if (HAL_UART_Init(&huart2) != HAL_OK)
  {
    Error_Handler();
  }
  if (HAL_UARTEx_SetTxFifoThreshold(&huart2, UART_TXFIFO_THRESHOLD_1_8) != HAL_OK)
  {
    Error_Handler();
  }
  if (HAL_UARTEx_SetRxFifoThreshold(&huart2, UART_RXFIFO_THRESHOLD_1_8) != HAL_OK)
  {
    Error_Handler();
  }
  if (HAL_UARTEx_DisableFifoMode(&huart2) != HAL_OK)
  {
    Error_Handler();
  }

}

static void MX_GPIO_Init(void)
{
  GPIO_InitTypeDef GPIO_InitStruct = {0};

  /* GPIO Ports Clock Enable */
  __HAL_RCC_GPIOC_CLK_ENABLE();
  __HAL_RCC_GPIOH_CLK_ENABLE();
  __HAL_RCC_GPIOA_CLK_ENABLE();
  __HAL_RCC_GPIOB_CLK_ENABLE();
  __HAL_RCC_GPIOD_CLK_ENABLE();
  __HAL_RCC_GPIOE_CLK_ENABLE();

  /*Configure GPIO pin Output Level */
  HAL_GPIO_WritePin(GPIOB, START_LED_RED_Pin|START_LED_GREEN_Pin|START_LED_BLUE_Pin, GPIO_PIN_RESET);

  /*Configure GPIO pin Output Level */
  HAL_GPIO_WritePin(DR1_EN_GPIO_Port, DR1_EN_Pin, GPIO_PIN_RESET);

  /*Configure GPIO pin Output Level */
  HAL_GPIO_WritePin(DR2_EN_GPIO_Port, DR2_EN_Pin, GPIO_PIN_RESET);

  /*Configure GPIO pin : START_MOD_IR1_Pin */
  GPIO_InitStruct.Pin = START_MOD_IR1_Pin;
  GPIO_InitStruct.Mode = GPIO_MODE_IT_RISING;
  GPIO_InitStruct.Pull = GPIO_NOPULL;
  HAL_GPIO_Init(START_MOD_IR1_GPIO_Port, &GPIO_InitStruct);

  /*Configure GPIO pins : START_LED_RED_Pin START_LED_GREEN_Pin START_LED_BLUE_Pin */
  GPIO_InitStruct.Pin = START_LED_RED_Pin|START_LED_GREEN_Pin|START_LED_BLUE_Pin;
  GPIO_InitStruct.Mode = GPIO_MODE_OUTPUT_PP;
  GPIO_InitStruct.Pull = GPIO_NOPULL;
  GPIO_InitStruct.Speed = GPIO_SPEED_FREQ_LOW;
  HAL_GPIO_Init(GPIOB, &GPIO_InitStruct);

  /*Configure GPIO pin : START_MOD_IR3_Pin */
  GPIO_InitStruct.Pin = START_MOD_IR3_Pin;
  GPIO_InitStruct.Mode = GPIO_MODE_IT_RISING;
  GPIO_InitStruct.Pull = GPIO_NOPULL;
  HAL_GPIO_Init(START_MOD_IR3_GPIO_Port, &GPIO_InitStruct);

  /*Configure GPIO pins : JOY5_Pin JOY4_Pin */
  GPIO_InitStruct.Pin = JOY5_Pin|JOY4_Pin;
  GPIO_InitStruct.Mode = GPIO_MODE_INPUT;
  GPIO_InitStruct.Pull = GPIO_NOPULL;
  HAL_GPIO_Init(GPIOD, &GPIO_InitStruct);

  /*Configure GPIO pins : JOY3_Pin JOY2_Pin JOY1_Pin */
  GPIO_InitStruct.Pin = JOY3_Pin|JOY2_Pin|JOY1_Pin;
  GPIO_InitStruct.Mode = GPIO_MODE_INPUT;
  GPIO_InitStruct.Pull = GPIO_NOPULL;
  HAL_GPIO_Init(GPIOC, &GPIO_InitStruct);

  /*Configure GPIO pin : DR1_EN_Pin */
  GPIO_InitStruct.Pin = DR1_EN_Pin;
  GPIO_InitStruct.Mode = GPIO_MODE_OUTPUT_PP;
  GPIO_InitStruct.Pull = GPIO_NOPULL;
  GPIO_InitStruct.Speed = GPIO_SPEED_FREQ_LOW;
  HAL_GPIO_Init(DR1_EN_GPIO_Port, &GPIO_InitStruct);

  /*Configure GPIO pin : DR2_EN_Pin */
  GPIO_InitStruct.Pin = DR2_EN_Pin;
  GPIO_InitStruct.Mode = GPIO_MODE_OUTPUT_PP;
  GPIO_InitStruct.Pull = GPIO_NOPULL;
  GPIO_InitStruct.Speed = GPIO_SPEED_FREQ_LOW;
  HAL_GPIO_Init(DR2_EN_GPIO_Port, &GPIO_InitStruct);

  /*Configure GPIO pin : START_MOD_IR_2_Pin */
  GPIO_InitStruct.Pin = START_MOD_IR_2_Pin;
  GPIO_InitStruct.Mode = GPIO_MODE_IT_RISING;
  GPIO_InitStruct.Pull = GPIO_NOPULL;
  HAL_GPIO_Init(START_MOD_IR_2_GPIO_Port, &GPIO_InitStruct);

}

/* USER CODE BEGIN 4 */
void HAL_TIM_PeriodElapsedCallback(TIM_HandleTypeDef *htim)
{
	if(htim->Instance == TIM16) //0.5Hz leds!
	{
		LED_BLINK_INTERUPT();
	}
	if(htim->Instance == TIM16) //1000Hz battlee
	{
	  GET_LINE_SENSORS();
	  GET_LAST_SEEN_ROTATIONE();
	  GET_START_MOD();
	  if(Eva.State == IDLE)
	  {
		  //BATTLE();
	  }
	  if(Eva.State == ATTACK)
	  {
		  //BATTLE();
	  }
	  else if(Eva.State == BEFORE_ATTACK_TASK)
	  {
		  TASK_BEFORE_ATTACK();
	  }
	}

	if(htim->Instance == TIM17) //100hz everything else
	{
	   WATCHDOG();
	}
}

void LED_BLINK_INTERUPT()
{
	if (FLAG_BLINK_RED == 1)
		HAL_GPIO_TogglePin(START_LED_RED_GPIO_Port, START_LED_RED_Pin);
	else
		HAL_GPIO_WritePin(START_LED_RED_GPIO_Port, START_LED_RED_Pin, 0);

	if (FLAG_BLINK_BLUE == 1)
		HAL_GPIO_TogglePin(START_LED_BLUE_GPIO_Port, START_LED_BLUE_Pin);
	else
		HAL_GPIO_WritePin(START_LED_BLUE_GPIO_Port, START_LED_BLUE_Pin, 0);

	if (FLAG_BLINK_GREEN == 1)
		HAL_GPIO_TogglePin(START_LED_GREEN_GPIO_Port, START_LED_GREEN_Pin);
	else
		HAL_GPIO_WritePin(START_LED_GREEN_GPIO_Port, START_LED_GREEN_Pin, 0);

	FLAG_BLINK_RED = 0;
	FLAG_BLINK_BLUE = 0;
	FLAG_BLINK_GREEN = 0;
}

void TASK_BEFORE_ATTACK()
{
	typedef enum {
		ZERO,
		START_WAIT_DELAY,
		INITIAL_ROTATION,
		GO_TO_THE_EDGE,
	} Stage_t;
	static Stage_t taskStage = START_WAIT_DELAY;
	static uint16_t StartDelayTimer=0;

	if(taskStage == ZERO)
	{
		StartDelayTimer=0;
		taskStage = START_WAIT_DELAY;
	}

	if(taskStage == START_WAIT_DELAY)
	{
		StartDelayTimer++;
		if(StartDelayTimer > START_WAITING_TIME)
			taskStage = INITIAL_ROTATION;
	}

	if(taskStage == INITIAL_ROTATION)
	{
		if(before_attack_rotation_direction == LEFT)
		{
			SET_MOTORS(-ROTATE_BEFORE_TASK_SPEED, ROTATE_BEFORE_TASK_SPEED);
			if (BackLeft.Distance < ACKNOWLEDGE_LIDAR_DISTANCE)
			{
				taskStage = GO_TO_THE_EDGE;
			}
		}
		else
		{
			SET_MOTORS(ROTATE_BEFORE_TASK_SPEED, -ROTATE_BEFORE_TASK_SPEED);
			if (BackRight.Distance < ACKNOWLEDGE_LIDAR_DISTANCE)
			{
				taskStage = GO_TO_THE_EDGE;
			}
		}
	}

	if(taskStage == GO_TO_THE_EDGE)
	{
		SET_MOTORS(-GO_TO_LINE_TASK_SPEED, -GO_TO_LINE_TASK_SPEED);
		if(BackLeft.Line == OUT || BackRight.Line == OUT) //reszta? todo
		{
			taskStage = ZERO;
			Eva.State = ATTACK;
		}
	}

}

void SET_MOTORS(int8_t l, int8_t r)
{

	if(Settings.DONT_USE_MOTORS)
		l = r = 0;

	if (SWITCH_MOTORS)
	{
	    int8_t tmp = l;
	    l = r;
	    r = tmp;
	}
	if(REVERSE_RIGHT_MOTOR)
	{
		r = -r;
	}
	if(REVERSE_LEFT_MOTOR)
	{
		l = -l;
	}

	l = l * LEFT_MOTOR_SPEED_MULTIPLIER;
	r = r * RIGHT_MOTOR_SPEED_MULTIPLIER;
}

void GET_LAST_SEEN_ROTATIONE()
{
	if(Eva.State == IDLE)
	{
		if(FrontLeft.Distance <= MIN_LIDAR_DISTANCE)
			lastSeen = LEFT;
		else if(FrontRight.Distance <= MIN_LIDAR_DISTANCE)
			lastSeen = RIGHT;
	}
	else
	{
		if(FrontLeft.Distance <= MAX_LIDAR_DISTANCE)
			lastSeen = LEFT;
		else if(FrontRight.Distance <= MAX_LIDAR_DISTANCE)
			lastSeen = RIGHT;
	}

}

void GET_START_MOD()
{
	Eva.State = IDLE;

	if(false)
	{
		before_attack_rotation_direction = lastSeen;
        Eva.State = BEFORE_ATTACK_TASK;
	}
}

void BATTLE()
{
	//67
}

void COOKED(uint8_t error_code)
//error flag codes less than 200 has priority and HALT
{
	  //TODO buzzer?
	  if(error_code < 200)
	  {
		  ERROR_FLAG = error_code;
		  Error_Handler();
	  }
	  else
	  {
		  ERROR_FLAG = error_code;
	  }
}

void HAL_FDCAN_RxFifo0Callback(FDCAN_HandleTypeDef *hfdcan, uint32_t RxFifo0ITs)
{

	HAL_FDCAN_GetRxMessage(hfdcan, FDCAN_RX_FIFO0, &CAN_RX_Header, CAN_RX);
	HAL_FDCAN_ActivateNotification(hfdcan, FDCAN_IT_RX_FIFO0_NEW_MESSAGE, 0);
}

void LIDARS_INIT(UART_HandleTypeDef *huart, DMA_HandleTypeDef *dma, uint8_t *RX)
{
	uint8_t counter=0;

	//LIDARS OFF
	UART_TX[0] = 0x5A;
	UART_TX[1] = 0x05;
	UART_TX[2] = 0x07;
	UART_TX[3] = 0x00;
	UART_TX[4] = (UART_TX[0] + UART_TX[1] + UART_TX[2] + UART_TX[3]) % 0x100;
	counter=0;
	while(true)
	{
		HAL_UART_Transmit(huart, UART_TX, 5, LIDARS_INIT_UART_TIMEOUT);
		HAL_UART_Receive(huart, RX, 5, LIDARS_INIT_UART_TIMEOUT);

		if(RX[0] == UART_TX[0] && RX[1] == UART_TX[1] && RX[2] == UART_TX[2])
			break;
		if(counter >= MAX_RETRIES_LIDARS_INIT)
			COOKED(LIDARS_INIT_ERR);
		counter++;
	}
	counter=0;
	HAL_Delay(50);

	//LIDARS SET 250Hz
	UART_TX[0] = 0x5A;
	UART_TX[1] = 0x06;
	UART_TX[2] = 0x03;
	UART_TX[3] = 0xFA;
	UART_TX[4] = 0x00;
	UART_TX[5] = (UART_TX[0] + UART_TX[1] + UART_TX[2] + UART_TX[3]) % 0x100;
	counter=0;
	while(true)
	{
		HAL_UART_Transmit(huart, UART_TX, 6, LIDARS_INIT_UART_TIMEOUT);
		HAL_UART_Receive(huart, RX, 6, LIDARS_INIT_UART_TIMEOUT);

		if(RX[0] == UART_TX[0] && RX[1] == UART_TX[1] && RX[2] == UART_TX[2])
			break;
		if(counter >= MAX_RETRIES_LIDARS_INIT)
			COOKED(LIDARS_INIT_ERR);
		counter++;
	}
	counter=0;
	HAL_Delay(50);

	//LIDARS ON
	UART_TX[0] = 0x5A;
	UART_TX[1] = 0x05;
	UART_TX[2] = 0x07;
	UART_TX[3] = 0x01;
	UART_TX[4] = (UART_TX[0] + UART_TX[1] + UART_TX[2] + UART_TX[3]) % 0x100;
	counter=0;
	while(true)
	{
		HAL_UART_Transmit(huart, UART_TX, 5, LIDARS_INIT_UART_TIMEOUT);
		HAL_UART_Receive(huart, RX, 5, LIDARS_INIT_UART_TIMEOUT);

		if(RX[0] == UART_TX[0] && RX[1] == UART_TX[1] && RX[2] == UART_TX[2])
			break;
		if(counter >= MAX_RETRIES_LIDARS_INIT)
			COOKED(LIDARS_INIT_ERR);
		counter++;
	}
	HAL_Delay(50);

	counter=0;
	while(true)
	{

		if(huart->RxState == HAL_UART_STATE_READY && huart->gState == HAL_UART_STATE_READY && huart->ErrorCode == HAL_UART_ERROR_NONE)
			break;
		else if(counter >= MAX_RETRIES_LIDARS_INIT)
			COOKED(LIDARS_INIT_ERR);

		HAL_Delay(LIDARS_INIT_UART_TIMEOUT);
		counter++;
	}

	HAL_Delay(50);

	HAL_UART_AbortReceive(huart);
	__HAL_UART_CLEAR_OREFLAG(huart);
	huart->ErrorCode = HAL_UART_ERROR_NONE;
	huart->RxState   = HAL_UART_STATE_READY;
	if(HAL_UARTEx_ReceiveToIdle_DMA(huart, RX, 9) != HAL_OK)
		COOKED(LIDARS_INIT_ERR);
	__HAL_DMA_DISABLE_IT(dma, DMA_IT_HT);

}

void PLAY_FREQ(uint16_t f_hz)
{
	f_hz = f_hz * ENABLE_BUZZER;
    if (f_hz == 0) {
        __HAL_TIM_SET_COMPARE(&htim3, TIM_CHANNEL_1, 0);
        return;
    }

    // Stały PSC=169 -> licznik 1 MHz (TIMCLK 170 MHz / (169+1))
    __HAL_TIM_SET_PRESCALER(&htim3, 169);

    uint32_t arr = 1000000UL / f_hz;            // okres w tickach 1 MHz
    if (arr == 0) arr = 1;                      // minimalna wartość
    arr -= 1;                                   // rejestrowo

    __HAL_TIM_DISABLE(&htim3);
    __HAL_TIM_SET_AUTORELOAD(&htim3, (uint16_t)arr);
    __HAL_TIM_SET_COMPARE(&htim3, TIM_CHANNEL_1, (uint16_t)(((arr + 1U) >> 1)));
    __HAL_TIM_SET_COUNTER(&htim3, 0);
    __HAL_TIM_ENABLE(&htim3);
    HAL_TIM_PWM_Start(&htim3, TIM_CHANNEL_1);
}

void HAL_UARTEx_RxEventCallback(UART_HandleTypeDef *huart, uint16_t Size)
{
	uint16_t buffor_Dist[LIDARS_FILTERING_ARRAY_SIZE];
	uint16_t buffor_Amp[LIDARS_FILTERING_ARRAY_SIZE];
	uint16_t Dist, Temp, Amp;
	uint8_t j, k;

	if(huart->Instance == USART1)
	{
		for (int i = 1; i < 10; i++)
		{
			if (UART1_RX[(i-1)% 9] == 0x59 && UART1_RX[i%9] == 0x59)
			{
				//DISTANCE
				j = (i + 1) % 9;
				k = (i + 2) % 9;
				Dist = UART1_RX[j] + (UART1_RX[k] << 8);

				//AMPERAGE
				j = (i + 3) % 9;
				k = (i + 4) % 9;
				Amp = UART1_RX[j] + (UART1_RX[k] << 8);

				//TEMPERATURE
				j = (i + 5) % 9;
				k = (i + 6) % 9;
				Temp = UART1_RX[j] + (UART1_RX[k] << 8);

				if(Amp < MIN_AMP_TRESCHOLD)
				{
					Dist = 65000;
				}

				break;
			}
		}

		//=====MEDIAN FILTERING
		static uint16_t window1_Dist[LIDARS_FILTERING_ARRAY_SIZE];
		static uint16_t window1_Amp[LIDARS_FILTERING_ARRAY_SIZE];
		static uint8_t idx1_Dist = 0;
		static uint8_t idx1_Amp = 0;

		//Wstaw nowe wartosci
		window1_Dist[idx1_Dist] = Dist;
		window1_Amp[idx1_Amp] = Amp;

		//Przesun indeksy cyklicznie
		idx1_Dist = (idx1_Dist + 1) % LIDARS_FILTERING_ARRAY_SIZE;
		idx1_Amp = (idx1_Amp + 1) % LIDARS_FILTERING_ARRAY_SIZE;

		//Kopiuj i sortuj w jednej petli
		for (int i = 0; i < LIDARS_FILTERING_ARRAY_SIZE; i++) {
			buffor_Dist[i] = window1_Dist[i];
			buffor_Amp[i] = window1_Amp[i];
		}

		//Sortuj osobno
		SORT(buffor_Dist, LIDARS_FILTERING_ARRAY_SIZE);
		SORT(buffor_Amp, LIDARS_FILTERING_ARRAY_SIZE);

		//Wyciagnij mediany
		Dist = buffor_Dist[(uint8_t)((LIDARS_FILTERING_ARRAY_SIZE - 1) / 2)];
		Amp = buffor_Amp[(uint8_t)((LIDARS_FILTERING_ARRAY_SIZE - 1) / 2)];

		//Save results
		FrontRight.Distance = Dist;
		FrontRight.LidarAmp = Amp;
		FrontRight.LidarTemp = Temp;

		if(HAL_UARTEx_ReceiveToIdle_DMA(&huart1, UART1_RX, 9) != HAL_OK)
			COOKED(LIDARS_INIT_ERR);
		__HAL_DMA_DISABLE_IT(DMA_HANDLE_UART1, DMA_IT_HT);
	}

	if(huart->Instance == USART2)
		{
			for (int i = 1; i < 10; i++)
			{
				if (UART2_RX[(i-1)% 9] == 0x59 && UART2_RX[i%9] == 0x59)
				{
					//DISTANCE
					j = (i + 1) % 9;
					k = (i + 2) % 9;
					Dist = UART2_RX[j] + (UART2_RX[k] << 8);

					//AMPERAGE
					j = (i + 3) % 9;
					k = (i + 4) % 9;
					Amp = UART2_RX[j] + (UART2_RX[k] << 8);

					//TEMPERATURE
					j = (i + 5) % 9;
					k = (i + 6) % 9;
					Temp = UART2_RX[j] + (UART2_RX[k] << 8);

					if(Amp < MIN_AMP_TRESCHOLD)
					{
						Dist = 65000;
					}

					break;
				}
			}

			//=====MEDIAN FILTERING
			static uint16_t window2_Dist[LIDARS_FILTERING_ARRAY_SIZE];
			static uint16_t window2_Amp[LIDARS_FILTERING_ARRAY_SIZE];
			static uint8_t idx2_Dist = 0;
			static uint8_t idx2_Amp = 0;

			//Wstaw nowe wartosci
			window2_Dist[idx2_Dist] = Dist;
			window2_Amp[idx2_Amp] = Amp;

			//Przesun indeksy cyklicznie
			idx2_Dist = (idx2_Dist + 1) % LIDARS_FILTERING_ARRAY_SIZE;
			idx2_Amp = (idx2_Amp + 1) % LIDARS_FILTERING_ARRAY_SIZE;

			//Kopiuj i sortuj w jednej petli
			for (int i = 0; i < LIDARS_FILTERING_ARRAY_SIZE; i++) {
				buffor_Dist[i] = window2_Dist[i];
				buffor_Amp[i] = window2_Amp[i];
			}

			//Sortuj osobno
			SORT(buffor_Dist, LIDARS_FILTERING_ARRAY_SIZE);
			SORT(buffor_Amp, LIDARS_FILTERING_ARRAY_SIZE);

			//Wyciagnij mediany
			Dist = buffor_Dist[(uint8_t)((LIDARS_FILTERING_ARRAY_SIZE - 1) / 2)];
			Amp = buffor_Amp[(uint8_t)((LIDARS_FILTERING_ARRAY_SIZE - 1) / 2)];

			//Save results
			FrontLeft.Distance = Dist;
			FrontLeft.LidarAmp = Amp;
			FrontLeft.LidarTemp = Temp;

			if(HAL_UARTEx_ReceiveToIdle_DMA(&huart2, UART2_RX, 9) != HAL_OK)
				COOKED(LIDARS_INIT_ERR);
			__HAL_DMA_DISABLE_IT(DMA_HANDLE_UART2, DMA_IT_HT);
		}

	if(huart->Instance == UART4)
			{
				for (int i = 1; i < 10; i++)
				{
					if (UART4_RX[(i-1)% 9] == 0x59 && UART4_RX[i%9] == 0x59)
					{
						//DISTANCE
						j = (i + 1) % 9;
						k = (i + 2) % 9;
						Dist = UART4_RX[j] + (UART4_RX[k] << 8);

						//AMPERAGE
						j = (i + 3) % 9;
						k = (i + 4) % 9;
						Amp = UART4_RX[j] + (UART4_RX[k] << 8);

						//TEMPERATURE
						j = (i + 5) % 9;
						k = (i + 6) % 9;
						Temp = UART4_RX[j] + (UART4_RX[k] << 8);

						if(Amp < MIN_AMP_TRESCHOLD)
						{
							Dist = 65000;
						}

						break;
					}
				}

				//=====MEDIAN FILTERING
				static uint16_t window4_Dist[LIDARS_FILTERING_ARRAY_SIZE];
				static uint16_t window4_Amp[LIDARS_FILTERING_ARRAY_SIZE];
				static uint8_t idx4_Dist = 0;
				static uint8_t idx4_Amp = 0;

				//Wstaw nowe wartosci
				window4_Dist[idx4_Dist] = Dist;
				window4_Amp[idx4_Amp] = Amp;

				//Przesun indeksy cyklicznie
				idx4_Dist = (idx4_Dist + 1) % LIDARS_FILTERING_ARRAY_SIZE;
				idx4_Amp = (idx4_Amp + 1) % LIDARS_FILTERING_ARRAY_SIZE;

				//Kopiuj i sortuj w jednej petli
				for (int i = 0; i < LIDARS_FILTERING_ARRAY_SIZE; i++) {
					buffor_Dist[i] = window4_Dist[i];
					buffor_Amp[i] = window4_Amp[i];
				}

				//Sortuj osobno
				SORT(buffor_Dist, LIDARS_FILTERING_ARRAY_SIZE);
				SORT(buffor_Amp, LIDARS_FILTERING_ARRAY_SIZE);

				//Wyciagnij mediany
				Dist = buffor_Dist[(uint8_t)((LIDARS_FILTERING_ARRAY_SIZE - 1) / 2)];
				Amp = buffor_Amp[(uint8_t)((LIDARS_FILTERING_ARRAY_SIZE - 1) / 2)];

				//Save results
				BackLeft.Distance = Dist;
				BackLeft.LidarAmp = Amp;
				BackLeft.LidarTemp = Temp;

				if(HAL_UARTEx_ReceiveToIdle_DMA(&huart4, UART4_RX, 9) != HAL_OK)
					COOKED(LIDARS_INIT_ERR);
				__HAL_DMA_DISABLE_IT(DMA_HANDLE_UART4, DMA_IT_HT);
			}

	if(huart->Instance == UART5)
			{
				for (int i = 1; i < 10; i++)
				{
					if (UART5_RX[(i-1)% 9] == 0x59 && UART5_RX[i%9] == 0x59)
					{
						//DISTANCE
						j = (i + 1) % 9;
						k = (i + 2) % 9;
						Dist = UART5_RX[j] + (UART5_RX[k] << 8);

						//AMPERAGE
						j = (i + 3) % 9;
						k = (i + 4) % 9;
						Amp = UART5_RX[j] + (UART5_RX[k] << 8);

						//TEMPERATURE
						j = (i + 5) % 9;
						k = (i + 6) % 9;
						Temp = UART5_RX[j] + (UART5_RX[k] << 8);

						if(Amp < MIN_AMP_TRESCHOLD)
						{
							Dist = 65000;
						}

						break;
					}
				}

				//=====MEDIAN FILTERING
				static uint16_t window5_Dist[LIDARS_FILTERING_ARRAY_SIZE];
				static uint16_t window5_Amp[LIDARS_FILTERING_ARRAY_SIZE];
				static uint8_t idx5_Dist = 0;
				static uint8_t idx5_Amp = 0;

				//Wstaw nowe wartosci
				window5_Dist[idx5_Dist] = Dist;
				window5_Amp[idx5_Amp] = Amp;

				//Przesun indeksy cyklicznie
				idx5_Dist = (idx5_Dist + 1) % LIDARS_FILTERING_ARRAY_SIZE;
				idx5_Amp = (idx5_Amp + 1) % LIDARS_FILTERING_ARRAY_SIZE;

				//Kopiuj i sortuj w jednej petli
				for (int i = 0; i < LIDARS_FILTERING_ARRAY_SIZE; i++) {
					buffor_Dist[i] = window5_Dist[i];
					buffor_Amp[i] = window5_Amp[i];
				}

				//Sortuj osobno
				SORT(buffor_Dist, LIDARS_FILTERING_ARRAY_SIZE);
				SORT(buffor_Amp, LIDARS_FILTERING_ARRAY_SIZE);

				//Wyciagnij mediany
				Dist = buffor_Dist[(uint8_t)((LIDARS_FILTERING_ARRAY_SIZE - 1) / 2)];
				Amp = buffor_Amp[(uint8_t)((LIDARS_FILTERING_ARRAY_SIZE - 1) / 2)];

				//Save results
				BackRight.Distance = Dist;
				BackRight.LidarAmp = Amp;
				BackRight.LidarTemp = Temp;

				if(HAL_UARTEx_ReceiveToIdle_DMA(&huart5, UART5_RX, 9) != HAL_OK)
					COOKED(LIDARS_INIT_ERR);
				__HAL_DMA_DISABLE_IT(DMA_HANDLE_UART5, DMA_IT_HT);
			}

}

void SORT(uint16_t *array, uint8_t length) {
    for (int i = 0; i < length - 1; i++) {
        for (int j = 0; j < length - 1 - i; j++) {
            if (array[j] > array[j + 1]) {
                uint16_t temp = array[j];
                array[j] = array[j + 1];
                array[j + 1] = temp;
            }
        }
    }
}

void GET_LINE_SENSORS()
{
	FrontLeft.Line = IN;
	FrontLeft.RawLineA = ADC_BUFFER[0];
	FrontLeft.RawLineB = ADC_BUFFER[1];

	FrontRight.Line = IN;
	FrontRight.RawLineA = ADC_BUFFER[2];
	FrontRight.RawLineB = ADC_BUFFER[3];

	BackLeft.Line = IN;
	BackLeft.RawLineA = ADC_BUFFER[4];
	BackLeft.RawLineB = ADC_BUFFER[5];

	BackRight.Line = IN;
	BackRight.RawLineA = ADC_BUFFER[6];
	BackRight.RawLineB = ADC_BUFFER[8];

	if(FrontLeft.RawLineA < WHITE_LINE_TRESCHOLD && FrontLeft.RawLineB < WHITE_LINE_TRESCHOLD)
		FrontLeft.Line = OUT;

	if(FrontRight.RawLineA < WHITE_LINE_TRESCHOLD && FrontRight.RawLineB < WHITE_LINE_TRESCHOLD)
		FrontRight.Line = OUT;

	if(BackLeft.RawLineA < WHITE_LINE_TRESCHOLD && BackLeft.RawLineB < WHITE_LINE_TRESCHOLD)
		BackLeft.Line = OUT;

	if(BackRight.RawLineA < WHITE_LINE_TRESCHOLD && BackRight.RawLineB < WHITE_LINE_TRESCHOLD)
		BackRight.Line = OUT;

}

void WATCHDOG()
{
	Eva.Voltage = ADC_BUFFER[7] * BATTERY_CONSTANT * BATTERY_VOLTAGE_COMPENSATION;
	Eva.CellVoltage = Eva.AttackMode / 3;
	if(Eva.CellVoltage < MIN_BATTERY_VOLTAGE_PER_CELL)
		FLAG_BLINK_BLUE = 1;
}
/* USER CODE END 4 */

void Error_Handler(void)
{
  /* USER CODE BEGIN Error_Handler_Debug */
	HAL_GPIO_WritePin(START_LED_RED_GPIO_Port, START_LED_RED_Pin, 1);
	HAL_Delay(10);
  /* User can add his own implementation to report the HAL error return state */
  __disable_irq();
  while (1)
  {
  }
  /* USER CODE END Error_Handler_Debug */
}
